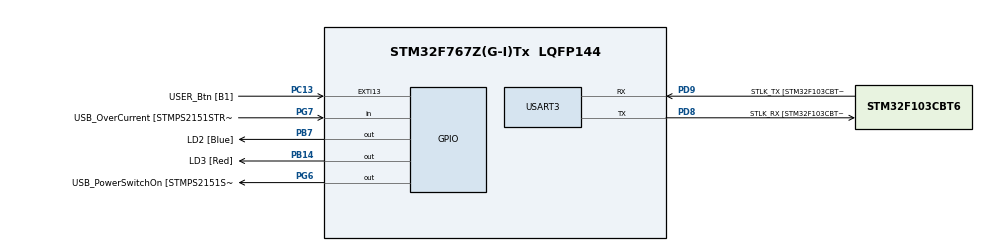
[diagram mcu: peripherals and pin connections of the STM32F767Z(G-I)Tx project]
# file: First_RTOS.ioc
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FREERTOS.Tasks01=defaultTask,0,128,StartDefaultTask,Default,NULL
Mcu.Family=STM32F7
Mcu.Name=STM32F767Z(G-I)Tx
Mcu.Package=LQFP144
NVIC.PriorityGroup=NVIC_PRIORITYGROUP_4
NVIC.TIM1_UP_TIM10_IRQn=true\:0\:0\:false\:false\:true\:false
NVIC.TimeBase=TIM1_UP_TIM10_IRQn
NVIC.TimeBaseIP=TIM1
PA1.GPIO_Label=RMII_REF_CLK [LAN8742A-CZ-TR_REFCLK0]
PA1.Signal=ETH_REF_CLK
PA10.GPIO_Label=USB_ID
PA10.Signal=USB_OTG_FS_ID
PA11.GPIO_Label=USB_DM
PA11.Signal=USB_OTG_FS_DM
PA12.GPIO_Label=USB_DP
PA12.Signal=USB_OTG_FS_DP
PA13.GPIO_Label=TMS
PA13.Signal=SYS_JTMS-SWDIO
PA14.GPIO_Label=TCK
PA14.Signal=SYS_JTCK-SWCLK
PA2.GPIO_Label=RMII_MDIO [LAN8742A-CZ-TR_MDIO]
PA2.Signal=ETH_MDIO
PA7.GPIO_Label=RMII_CRS_DV [LAN8742A-CZ-TR_CRS_DV]
PA7.Signal=ETH_CRS_DV
PA8.GPIO_Label=USB_SOF [TP1]
PA8.Signal=USB_OTG_FS_SOF
PA9.GPIO_Label=USB_VBUS
PA9.Signal=USB_OTG_FS_VBUS
PB13.GPIO_Label=RMII_TXD1 [LAN8742A-CZ-TR_TXD1]
PB13.Signal=ETH_TXD1
PB14.GPIO_Label=LD3 [Red]
PB14.Signal=GPIO_Output
PB3.GPIO_Label=SW0
PB3.Signal=SYS_JTDO-SWO
PB7.GPIO_Label=LD2 [Blue]
PB7.Signal=GPIO_Output
PC1.GPIO_Label=RMII_MDC [LAN8742A-CZ-TR_MDC]
PC1.Signal=ETH_MDC
PC13.GPIO_Label=USER_Btn [B1]
PC13.Signal=GPXTI13
PC14/OSC32_IN.Signal=RCC_OSC32_IN
PC15/OSC32_OUT.Signal=RCC_OSC32_OUT
PC4.GPIO_Label=RMII_RXD0 [LAN8742A-CZ-TR_RXD0]
PC4.Signal=ETH_RXD0
PC5.GPIO_Label=RMII_RXD1 [LAN8742A-CZ-TR_RXD1]
PC5.Signal=ETH_RXD1
PD8.GPIO_Label=STLK_RX [STM32F103CBT6_PA3]
PD8.Mode=Asynchronous
PD8.Signal=USART3_TX
PD9.GPIO_Label=STLK_TX [STM32F103CBT6_PA2]
PD9.Mode=Asynchronous
PD9.Signal=USART3_RX
PG11.GPIO_Label=RMII_TX_EN [LAN8742A-CZ-TR_TXEN]
PG11.Signal=ETH_TX_EN
PG13.GPIO_Label=RMII_TXD0 [LAN8742A-CZ-TR_TXD0]
PG13.Signal=ETH_TXD0
PG6.GPIO_Label=USB_PowerSwitchOn [STMPS2151STR_EN]
PG6.Signal=GPIO_Output
PG7.GPIO_Label=USB_OverCurrent [STMPS2151STR_FAULT]
PG7.Signal=GPIO_Input
PH0/OSC_IN.GPIO_Label=MCO [STM32F103CBT6_PA8]
PH0/OSC_IN.Signal=RCC_OSC_IN
PH1/OSC_OUT.Signal=RCC_OSC_OUT
ProjectManager.HeapSize=0x200
ProjectManager.StackSize=0x400
ProjectManager.TargetToolchain=SW4STM32
RCC.48MHZClocksFreq_Value=24000000
RCC.AHBFreq_Value=216000000
RCC.APB1CLKDivider=RCC_HCLK_DIV4
RCC.APB1Freq_Value=54000000
RCC.APB1TimFreq_Value=108000000
RCC.APB2CLKDivider=RCC_HCLK_DIV2
RCC.APB2Freq_Value=108000000
RCC.APB2TimFreq_Value=216000000
RCC.CortexFreq_Value=216000000
RCC.HCLKFreq_Value=216000000
RCC.HSE_VALUE=16000000
RCC.HSI_VALUE=16000000
RCC.LSE_VALUE=32768
RCC.PLLM=8
RCC.PLLMUL=RCC_PLL_MUL9
RCC.PLLN=216
RCC.PRESCALERUSB=RCC_USBCLKSOURCE_PLL_DIV1_5
RCC.SYSCLKFreq_VALUE=216000000
RCC.SYSCLKSource=RCC_SYSCLKSOURCE_PLLCLK
RCC.SYSCLKSourceVirtual=RCC_SYSCLKSOURCE_PLLCLK
RCC.USART3CLockSelection=RCC_USART3CLKSOURCE_SYSCLK
RCC.USBFreq_Value=216000000
RCC.VCOOutputFreq_Value=432000000
USART3.VirtualMode-Asynchronous=VM_ASYNC
USART3.WordLength=WORDLENGTH_8B
VP_FREERTOS_VS_ENABLE.Mode=Enabled
VP_SYS_VS_tim1.Mode=TIM1
board=NUCLEO-F767ZI

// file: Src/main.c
/**
  ******************************************************************************
  * File Name          : main.c
  * Description        : Main program body
  ******************************************************************************
  * This notice applies to any and all portions of this file
  * that are not between comment pairs USER CODE BEGIN and
  * USER CODE END. Other portions of this file, whether
  * inserted by the user or by software development tools
  * are owned by their respective copyright owners.
  *
  * Copyright (c) 2017 STMicroelectronics International N.V.
  * All rights reserved.
  *
  * Redistribution and use in source and binary forms, with or without
  * modification, are permitted, provided that the following conditions are met:
  *
  * 1. Redistribution of source code must retain the above copyright notice,
  *    this list of conditions and the following disclaimer.
  * 2. Redistributions in binary form must reproduce the above copyright notice,
  *    this list of conditions and the following disclaimer in the documentation
  *    and/or other materials provided with the distribution.
  * 3. Neither the name of STMicroelectronics nor the names of other
  *    contributors to this software may be used to endorse or promote products
  *    derived from this software without specific written permission.
  * 4. This software, including modifications and/or derivative works of this
  *    software, must execute solely and exclusively on microcontroller or
  *    microprocessor devices manufactured by or for STMicroelectronics.
  * 5. Redistribution and use of this software other than as permitted under
  *    this license is void and will automatically terminate your rights under
  *    this license.
  *
  * THIS SOFTWARE IS PROVIDED BY STMICROELECTRONICS AND CONTRIBUTORS "AS IS"
  * AND ANY EXPRESS, IMPLIED OR STATUTORY WARRANTIES, INCLUDING, BUT NOT
  * LIMITED TO, THE IMPLIED WARRANTIES OF MERCHANTABILITY, FITNESS FOR A
  * PARTICULAR PURPOSE AND NON-INFRINGEMENT OF THIRD PARTY INTELLECTUAL PROPERTY
  * RIGHTS ARE DISCLAIMED TO THE FULLEST EXTENT PERMITTED BY LAW. IN NO EVENT
  * SHALL STMICROELECTRONICS OR CONTRIBUTORS BE LIABLE FOR ANY DIRECT, INDIRECT,
  * INCIDENTAL, SPECIAL, EXEMPLARY, OR CONSEQUENTIAL DAMAGES (INCLUDING, BUT NOT
  * LIMITED TO, PROCUREMENT OF SUBSTITUTE GOODS OR SERVICES; LOSS OF USE, DATA,
  * OR PROFITS; OR BUSINESS INTERRUPTION) HOWEVER CAUSED AND ON ANY THEORY OF
  * LIABILITY, WHETHER IN CONTRACT, STRICT LIABILITY, OR TORT (INCLUDING
  * NEGLIGENCE OR OTHERWISE) ARISING IN ANY WAY OUT OF THE USE OF THIS SOFTWARE,
  * EVEN IF ADVISED OF THE POSSIBILITY OF SUCH DAMAGE.
  *
  ******************************************************************************
  */
#include "main.h"
#include "stm32f7xx_hal.h"
#include "cmsis_os.h"
#include "usart.h"
#include "gpio.h"

/* USER CODE BEGIN PV */
/* Private variables ---------------------------------------------------------*/

/* USER CODE END PV */

void SystemClock_Config(void);
void MX_FREERTOS_Init(void);

/* USER CODE BEGIN PFP */
/* Private function prototypes -----------------------------------------------*/

/* USER CODE END PFP */

/* USER CODE BEGIN 0 */
void task1(void *p){
	while(1){
		HAL_UART_Transmit(&huart3, "Task1\n\r", 7, 10);
		vTaskDelay(4000);
	}
}

void task2(void *p){
	while(1){
		HAL_UART_Transmit(&huart3, "TASK2\n\r", 7, 10);
		vTaskDelay(2000);
	}
}
/* USER CODE END 0 */

int main(void)
{

  /* MCU Configuration----------------------------------------------------------*/

  /* Reset of all peripherals, Initializes the Flash interface and the Systick. */
  HAL_Init();

  /* Configure the system clock */
  SystemClock_Config();

  /* Initialize all configured peripherals */
  MX_GPIO_Init();
  MX_USART3_UART_Init();

  /* Call init function for freertos objects (in freertos.c) */
  MX_FREERTOS_Init();
  xTaskCreate(task1, (char *) "task1", 1024, NULL, 1, NULL);
  xTaskCreate(task2, (char *) "task2", 1024, NULL, 2, NULL);
  /* Start scheduler */
  osKernelStart();

  /* We should never get here as control is now taken by the scheduler */

  /* Infinite loop */
  while (1)
  {

  }

}

/** System Clock Configuration
*/
void SystemClock_Config(void)
{

  RCC_OscInitTypeDef RCC_OscInitStruct;
  RCC_ClkInitTypeDef RCC_ClkInitStruct;
  RCC_PeriphCLKInitTypeDef PeriphClkInitStruct;

    /**Configure the main internal regulator output voltage
    */
  __HAL_RCC_PWR_CLK_ENABLE();

  __HAL_PWR_VOLTAGESCALING_CONFIG(PWR_REGULATOR_VOLTAGE_SCALE3);

    /**Initializes the CPU, AHB and APB busses clocks
    */
  RCC_OscInitStruct.OscillatorType = RCC_OSCILLATORTYPE_HSI;
  RCC_OscInitStruct.HSIState = RCC_HSI_ON;
  RCC_OscInitStruct.HSICalibrationValue = 16;
  RCC_OscInitStruct.PLL.PLLState = RCC_PLL_NONE;
  if (HAL_RCC_OscConfig(&RCC_OscInitStruct) != HAL_OK)
  {
    _Error_Handler(__FILE__, __LINE__);
  }

    /**Initializes the CPU, AHB and APB busses clocks
    */
  RCC_ClkInitStruct.ClockType = RCC_CLOCKTYPE_HCLK|RCC_CLOCKTYPE_SYSCLK
                              |RCC_CLOCKTYPE_PCLK1|RCC_CLOCKTYPE_PCLK2;
  RCC_ClkInitStruct.SYSCLKSource = RCC_SYSCLKSOURCE_HSI;
  RCC_ClkInitStruct.AHBCLKDivider = RCC_SYSCLK_DIV1;
  RCC_ClkInitStruct.APB1CLKDivider = RCC_HCLK_DIV2;
  RCC_ClkInitStruct.APB2CLKDivider = RCC_HCLK_DIV1;

  if (HAL_RCC_ClockConfig(&RCC_ClkInitStruct, FLASH_LATENCY_0) != HAL_OK)
  {
    _Error_Handler(__FILE__, __LINE__);
  }

  PeriphClkInitStruct.PeriphClockSelection = RCC_PERIPHCLK_USART3;
  PeriphClkInitStruct.Usart3ClockSelection = RCC_USART3CLKSOURCE_PCLK1;
  if (HAL_RCCEx_PeriphCLKConfig(&PeriphClkInitStruct) != HAL_OK)
  {
    _Error_Handler(__FILE__, __LINE__);
  }

    /**Configure the Systick interrupt time
    */
  HAL_SYSTICK_Config(HAL_RCC_GetHCLKFreq()/1000);

    /**Configure the Systick
    */
  HAL_SYSTICK_CLKSourceConfig(SYSTICK_CLKSOURCE_HCLK);

  /* SysTick_IRQn interrupt configuration */
  HAL_NVIC_SetPriority(SysTick_IRQn, 15, 0);
}

void HAL_TIM_PeriodElapsedCallback(TIM_HandleTypeDef *htim)
{
  if (htim->Instance == TIM1) {
    HAL_IncTick();
  }
}

void _Error_Handler(char * file, int line)
{
  while(1)
  {
  }
}

/************************ (C) COPYRIGHT STMicroelectronics *****END OF FILE****/

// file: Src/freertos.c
/**
  ******************************************************************************
  * File Name          : freertos.c
  * Description        : Code for freertos applications
  ******************************************************************************
  * This notice applies to any and all portions of this file
  * that are not between comment pairs USER CODE BEGIN and
  * USER CODE END. Other portions of this file, whether
  * inserted by the user or by software development tools
  * are owned by their respective copyright owners.
  *
  * Copyright (c) 2017 STMicroelectronics International N.V.
  * All rights reserved.
  *
  * Redistribution and use in source and binary forms, with or without
  * modification, are permitted, provided that the following conditions are met:
  *
  * 1. Redistribution of source code must retain the above copyright notice,
  *    this list of conditions and the following disclaimer.
  * 2. Redistributions in binary form must reproduce the above copyright notice,
  *    this list of conditions and the following disclaimer in the documentation
  *    and/or other materials provided with the distribution.
  * 3. Neither the name of STMicroelectronics nor the names of other
  *    contributors to this software may be used to endorse or promote products
  *    derived from this software without specific written permission.
  * 4. This software, including modifications and/or derivative works of this
  *    software, must execute solely and exclusively on microcontroller or
  *    microprocessor devices manufactured by or for STMicroelectronics.
  * 5. Redistribution and use of this software other than as permitted under
  *    this license is void and will automatically terminate your rights under
  *    this license.
  *
  * THIS SOFTWARE IS PROVIDED BY STMICROELECTRONICS AND CONTRIBUTORS "AS IS"
  * AND ANY EXPRESS, IMPLIED OR STATUTORY WARRANTIES, INCLUDING, BUT NOT
  * LIMITED TO, THE IMPLIED WARRANTIES OF MERCHANTABILITY, FITNESS FOR A
  * PARTICULAR PURPOSE AND NON-INFRINGEMENT OF THIRD PARTY INTELLECTUAL PROPERTY
  * RIGHTS ARE DISCLAIMED TO THE FULLEST EXTENT PERMITTED BY LAW. IN NO EVENT
  * SHALL STMICROELECTRONICS OR CONTRIBUTORS BE LIABLE FOR ANY DIRECT, INDIRECT,
  * INCIDENTAL, SPECIAL, EXEMPLARY, OR CONSEQUENTIAL DAMAGES (INCLUDING, BUT NOT
  * LIMITED TO, PROCUREMENT OF SUBSTITUTE GOODS OR SERVICES; LOSS OF USE, DATA,
  * OR PROFITS; OR BUSINESS INTERRUPTION) HOWEVER CAUSED AND ON ANY THEORY OF
  * LIABILITY, WHETHER IN CONTRACT, STRICT LIABILITY, OR TORT (INCLUDING
  * NEGLIGENCE OR OTHERWISE) ARISING IN ANY WAY OUT OF THE USE OF THIS SOFTWARE,
  * EVEN IF ADVISED OF THE POSSIBILITY OF SUCH DAMAGE.
  *
  ******************************************************************************
  */

#include "FreeRTOS.h"
#include "task.h"
#include "cmsis_os.h"

osThreadId defaultTaskHandle;

void StartDefaultTask(void const * argument);

void MX_FREERTOS_Init(void); /* (MISRA C 2004 rule 8.1) */

/* Hook prototypes */

/* Init FreeRTOS */

void MX_FREERTOS_Init(void) {

  /* Create the thread(s) */
  /* definition and creation of defaultTask */
  osThreadDef(defaultTask, StartDefaultTask, osPriorityNormal, 0, 128);
  defaultTaskHandle = osThreadCreate(osThread(defaultTask), NULL);

}

/* StartDefaultTask function */
void StartDefaultTask(void const * argument)
{

  for(;;)
  {
    osDelay(1);
  }
}

/************************ (C) COPYRIGHT STMicroelectronics *****END OF FILE****/
